VERSION 5.7 ;
  NOWIREEXTENSIONATPIN ON ;
  DIVIDERCHAR "/" ;
  BUSBITCHARS "[]" ;
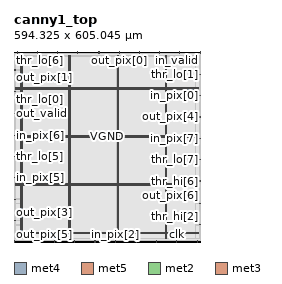
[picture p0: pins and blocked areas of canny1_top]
MACRO canny1_top
  CLASS BLOCK ;
  FOREIGN canny1_top ;
  ORIGIN 0.000 0.000 ;
  SIZE 594.325 BY 605.045 ;
  PIN VGND
    DIRECTION INOUT ;
    USE GROUND ;
    PORT
      LAYER met4 ;
        RECT 24.340 10.640 25.940 593.200 ;
    END
    PORT
      LAYER met4 ;
        RECT 177.940 10.640 179.540 593.200 ;
    END
    PORT
      LAYER met4 ;
        RECT 331.540 10.640 333.140 593.200 ;
    END
    PORT
      LAYER met4 ;
        RECT 485.140 10.640 486.740 593.200 ;
    END
    PORT
      LAYER met5 ;
        RECT 5.280 30.030 589.040 31.630 ;
    END
    PORT
      LAYER met5 ;
        RECT 5.280 183.210 589.040 184.810 ;
    END
    PORT
      LAYER met5 ;
        RECT 5.280 336.390 589.040 337.990 ;
    END
    PORT
      LAYER met5 ;
        RECT 5.280 489.570 589.040 491.170 ;
    END
  END VGND
  PIN VPWR
    DIRECTION INOUT ;
    USE POWER ;
    PORT
      LAYER met4 ;
        RECT 21.040 10.640 22.640 593.200 ;
    END
    PORT
      LAYER met4 ;
        RECT 174.640 10.640 176.240 593.200 ;
    END
    PORT
      LAYER met4 ;
        RECT 328.240 10.640 329.840 593.200 ;
    END
    PORT
      LAYER met4 ;
        RECT 481.840 10.640 483.440 593.200 ;
    END
    PORT
      LAYER met5 ;
        RECT 5.280 26.730 589.040 28.330 ;
    END
    PORT
      LAYER met5 ;
        RECT 5.280 179.910 589.040 181.510 ;
    END
    PORT
      LAYER met5 ;
        RECT 5.280 333.090 589.040 334.690 ;
    END
    PORT
      LAYER met5 ;
        RECT 5.280 486.270 589.040 487.870 ;
    END
  END VPWR
  PIN clk
    DIRECTION INPUT ;
    USE SIGNAL ;
    ANTENNAGATEAREA 1.286700 ;
    ANTENNADIFFAREA 0.434700 ;
    PORT
      LAYER met2 ;
        RECT 518.510 0.000 518.790 4.000 ;
    END
  END clk
  PIN in_pix[0]
    DIRECTION INPUT ;
    USE SIGNAL ;
    ANTENNAGATEAREA 0.126000 ;
    PORT
      LAYER met3 ;
        RECT 590.325 465.840 594.325 466.440 ;
    END
  END in_pix[0]
  PIN in_pix[1]
    DIRECTION INPUT ;
    USE SIGNAL ;
    ANTENNAGATEAREA 0.159000 ;
    PORT
      LAYER met2 ;
        RECT 138.550 601.045 138.830 605.045 ;
    END
  END in_pix[1]
  PIN in_pix[2]
    DIRECTION INPUT ;
    USE SIGNAL ;
    ANTENNAGATEAREA 0.213000 ;
    PORT
      LAYER met2 ;
        RECT 322.090 0.000 322.370 4.000 ;
    END
  END in_pix[2]
  PIN in_pix[3]
    DIRECTION INPUT ;
    USE SIGNAL ;
    ANTENNAGATEAREA 0.159000 ;
    PORT
      LAYER met2 ;
        RECT 193.290 0.000 193.570 4.000 ;
    END
  END in_pix[3]
  PIN in_pix[4]
    DIRECTION INPUT ;
    USE SIGNAL ;
    ANTENNAGATEAREA 0.213000 ;
    PORT
      LAYER met2 ;
        RECT 463.770 601.045 464.050 605.045 ;
    END
  END in_pix[4]
  PIN in_pix[5]
    DIRECTION INPUT ;
    USE SIGNAL ;
    ANTENNAGATEAREA 0.159000 ;
    PORT
      LAYER met3 ;
        RECT 0.000 204.040 4.000 204.640 ;
    END
  END in_pix[5]
  PIN in_pix[6]
    DIRECTION INPUT ;
    USE SIGNAL ;
    ANTENNAGATEAREA 0.213000 ;
    PORT
      LAYER met3 ;
        RECT 0.000 340.040 4.000 340.640 ;
    END
  END in_pix[6]
  PIN in_pix[7]
    DIRECTION INPUT ;
    USE SIGNAL ;
    ANTENNAGATEAREA 0.196500 ;
    PORT
      LAYER met3 ;
        RECT 590.325 329.840 594.325 330.440 ;
    END
  END in_pix[7]
  PIN in_valid
    DIRECTION INPUT ;
    USE SIGNAL ;
    ANTENNAGATEAREA 0.159000 ;
    PORT
      LAYER met2 ;
        RECT 592.570 601.045 592.850 605.045 ;
    END
  END in_valid
  PIN out_pix[0]
    DIRECTION OUTPUT TRISTATE ;
    USE SIGNAL ;
    ANTENNADIFFAREA 0.795200 ;
    PORT
      LAYER met2 ;
        RECT 334.970 601.045 335.250 605.045 ;
    END
  END out_pix[0]
  PIN out_pix[1]
    DIRECTION OUTPUT TRISTATE ;
    USE SIGNAL ;
    ANTENNADIFFAREA 0.795200 ;
    PORT
      LAYER met3 ;
        RECT 0.000 547.440 4.000 548.040 ;
    END
  END out_pix[1]
  PIN out_pix[2]
    DIRECTION OUTPUT TRISTATE ;
    USE SIGNAL ;
    ANTENNADIFFAREA 0.795200 ;
    PORT
      LAYER met2 ;
        RECT 582.910 0.000 583.190 4.000 ;
    END
  END out_pix[2]
  PIN out_pix[3]
    DIRECTION OUTPUT TRISTATE ;
    USE SIGNAL ;
    ANTENNADIFFAREA 0.795200 ;
    PORT
      LAYER met3 ;
        RECT 0.000 68.040 4.000 68.640 ;
    END
  END out_pix[3]
  PIN out_pix[4]
    DIRECTION OUTPUT TRISTATE ;
    USE SIGNAL ;
    ANTENNADIFFAREA 0.445500 ;
    PORT
      LAYER met3 ;
        RECT 590.325 397.840 594.325 398.440 ;
    END
  END out_pix[4]
  PIN out_pix[5]
    DIRECTION OUTPUT TRISTATE ;
    USE SIGNAL ;
    ANTENNADIFFAREA 0.795200 ;
    PORT
      LAYER met2 ;
        RECT 0.090 0.000 0.370 4.000 ;
    END
  END out_pix[5]
  PIN out_pix[6]
    DIRECTION OUTPUT TRISTATE ;
    USE SIGNAL ;
    ANTENNADIFFAREA 0.445500 ;
    PORT
      LAYER met3 ;
        RECT 590.325 122.440 594.325 123.040 ;
    END
  END out_pix[6]
  PIN out_pix[7]
    DIRECTION OUTPUT TRISTATE ;
    USE SIGNAL ;
    ANTENNADIFFAREA 0.795200 ;
    PORT
      LAYER met2 ;
        RECT 399.370 601.045 399.650 605.045 ;
    END
  END out_pix[7]
  PIN out_valid
    DIRECTION OUTPUT TRISTATE ;
    USE SIGNAL ;
    ANTENNADIFFAREA 0.795200 ;
    PORT
      LAYER met3 ;
        RECT 0.000 408.040 4.000 408.640 ;
    END
  END out_valid
  PIN reset
    DIRECTION INPUT ;
    USE SIGNAL ;
    ANTENNAGATEAREA 0.159000 ;
    PORT
      LAYER met2 ;
        RECT 74.150 601.045 74.430 605.045 ;
    END
  END reset
  PIN thr_hi[0]
    DIRECTION INPUT ;
    USE SIGNAL ;
    ANTENNAGATEAREA 0.196500 ;
    PORT
      LAYER met2 ;
        RECT 454.110 0.000 454.390 4.000 ;
    END
  END thr_hi[0]
  PIN thr_hi[1]
    DIRECTION INPUT ;
    USE SIGNAL ;
    ANTENNAGATEAREA 0.213000 ;
    PORT
      LAYER met2 ;
        RECT 528.170 601.045 528.450 605.045 ;
    END
  END thr_hi[1]
  PIN thr_hi[2]
    DIRECTION INPUT ;
    USE SIGNAL ;
    ANTENNAGATEAREA 0.213000 ;
    PORT
      LAYER met3 ;
        RECT 590.325 54.440 594.325 55.040 ;
    END
  END thr_hi[2]
  PIN thr_hi[3]
    DIRECTION INPUT ;
    USE SIGNAL ;
    ANTENNAGATEAREA 0.247500 ;
    PORT
      LAYER met2 ;
        RECT 64.490 0.000 64.770 4.000 ;
    END
  END thr_hi[3]
  PIN thr_hi[4]
    DIRECTION INPUT ;
    USE SIGNAL ;
    ANTENNAGATEAREA 0.213000 ;
    PORT
      LAYER met2 ;
        RECT 128.890 0.000 129.170 4.000 ;
    END
  END thr_hi[4]
  PIN thr_hi[5]
    DIRECTION INPUT ;
    USE SIGNAL ;
    ANTENNAGATEAREA 0.213000 ;
    PORT
      LAYER met3 ;
        RECT 0.000 136.040 4.000 136.640 ;
    END
  END thr_hi[5]
  PIN thr_hi[6]
    DIRECTION INPUT ;
    USE SIGNAL ;
    ANTENNAGATEAREA 0.213000 ;
    PORT
      LAYER met3 ;
        RECT 590.325 193.840 594.325 194.440 ;
    END
  END thr_hi[6]
  PIN thr_hi[7]
    DIRECTION INPUT ;
    USE SIGNAL ;
    ANTENNAGATEAREA 0.213000 ;
    PORT
      LAYER met2 ;
        RECT 257.690 0.000 257.970 4.000 ;
    END
  END thr_hi[7]
  PIN thr_lo[0]
    DIRECTION INPUT ;
    USE SIGNAL ;
    ANTENNAGATEAREA 0.247500 ;
    PORT
      LAYER met3 ;
        RECT 0.000 479.440 4.000 480.040 ;
    END
  END thr_lo[0]
  PIN thr_lo[1]
    DIRECTION INPUT ;
    USE SIGNAL ;
    ANTENNAGATEAREA 0.213000 ;
    PORT
      LAYER met3 ;
        RECT 590.325 533.840 594.325 534.440 ;
    END
  END thr_lo[1]
  PIN thr_lo[2]
    DIRECTION INPUT ;
    USE SIGNAL ;
    ANTENNAGATEAREA 0.247500 ;
    PORT
      LAYER met2 ;
        RECT 202.950 601.045 203.230 605.045 ;
    END
  END thr_lo[2]
  PIN thr_lo[3]
    DIRECTION INPUT ;
    USE SIGNAL ;
    ANTENNAGATEAREA 0.247500 ;
    PORT
      LAYER met2 ;
        RECT 270.570 601.045 270.850 605.045 ;
    END
  END thr_lo[3]
  PIN thr_lo[4]
    DIRECTION INPUT ;
    USE SIGNAL ;
    ANTENNAGATEAREA 0.213000 ;
    PORT
      LAYER met2 ;
        RECT 389.710 0.000 389.990 4.000 ;
    END
  END thr_lo[4]
  PIN thr_lo[5]
    DIRECTION INPUT ;
    USE SIGNAL ;
    ANTENNAGATEAREA 0.247500 ;
    PORT
      LAYER met3 ;
        RECT 0.000 272.040 4.000 272.640 ;
    END
  END thr_lo[5]
  PIN thr_lo[6]
    DIRECTION INPUT ;
    USE SIGNAL ;
    ANTENNAGATEAREA 0.426000 ;
    PORT
      LAYER met2 ;
        RECT 9.750 601.045 10.030 605.045 ;
    END
  END thr_lo[6]
  PIN thr_lo[7]
    DIRECTION INPUT ;
    USE SIGNAL ;
    ANTENNAGATEAREA 0.213000 ;
    PORT
      LAYER met3 ;
        RECT 590.325 261.840 594.325 262.440 ;
    END
  END thr_lo[7]
  OBS
      LAYER li1 ;
        RECT 5.520 10.795 588.800 593.045 ;
      LAYER met1 ;
        RECT 0.070 10.640 592.870 593.200 ;
      LAYER met2 ;
        RECT 0.100 600.765 9.470 601.045 ;
        RECT 10.310 600.765 73.870 601.045 ;
        RECT 74.710 600.765 138.270 601.045 ;
        RECT 139.110 600.765 202.670 601.045 ;
        RECT 203.510 600.765 270.290 601.045 ;
        RECT 271.130 600.765 334.690 601.045 ;
        RECT 335.530 600.765 399.090 601.045 ;
        RECT 399.930 600.765 463.490 601.045 ;
        RECT 464.330 600.765 527.890 601.045 ;
        RECT 528.730 600.765 592.290 601.045 ;
        RECT 0.100 4.280 592.840 600.765 ;
        RECT 0.650 4.000 64.210 4.280 ;
        RECT 65.050 4.000 128.610 4.280 ;
        RECT 129.450 4.000 193.010 4.280 ;
        RECT 193.850 4.000 257.410 4.280 ;
        RECT 258.250 4.000 321.810 4.280 ;
        RECT 322.650 4.000 389.430 4.280 ;
        RECT 390.270 4.000 453.830 4.280 ;
        RECT 454.670 4.000 518.230 4.280 ;
        RECT 519.070 4.000 582.630 4.280 ;
        RECT 583.470 4.000 592.840 4.280 ;
      LAYER met3 ;
        RECT 4.000 548.440 590.325 593.125 ;
        RECT 4.400 547.040 590.325 548.440 ;
        RECT 4.000 534.840 590.325 547.040 ;
        RECT 4.000 533.440 589.925 534.840 ;
        RECT 4.000 480.440 590.325 533.440 ;
        RECT 4.400 479.040 590.325 480.440 ;
        RECT 4.000 466.840 590.325 479.040 ;
        RECT 4.000 465.440 589.925 466.840 ;
        RECT 4.000 409.040 590.325 465.440 ;
        RECT 4.400 407.640 590.325 409.040 ;
        RECT 4.000 398.840 590.325 407.640 ;
        RECT 4.000 397.440 589.925 398.840 ;
        RECT 4.000 341.040 590.325 397.440 ;
        RECT 4.400 339.640 590.325 341.040 ;
        RECT 4.000 330.840 590.325 339.640 ;
        RECT 4.000 329.440 589.925 330.840 ;
        RECT 4.000 273.040 590.325 329.440 ;
        RECT 4.400 271.640 590.325 273.040 ;
        RECT 4.000 262.840 590.325 271.640 ;
        RECT 4.000 261.440 589.925 262.840 ;
        RECT 4.000 205.040 590.325 261.440 ;
        RECT 4.400 203.640 590.325 205.040 ;
        RECT 4.000 194.840 590.325 203.640 ;
        RECT 4.000 193.440 589.925 194.840 ;
        RECT 4.000 137.040 590.325 193.440 ;
        RECT 4.400 135.640 590.325 137.040 ;
        RECT 4.000 123.440 590.325 135.640 ;
        RECT 4.000 122.040 589.925 123.440 ;
        RECT 4.000 69.040 590.325 122.040 ;
        RECT 4.400 67.640 590.325 69.040 ;
        RECT 4.000 55.440 590.325 67.640 ;
        RECT 4.000 54.040 589.925 55.440 ;
        RECT 4.000 10.715 590.325 54.040 ;
      LAYER met4 ;
        RECT 19.615 11.735 20.640 592.105 ;
        RECT 23.040 11.735 23.940 592.105 ;
        RECT 26.340 11.735 174.240 592.105 ;
        RECT 176.640 11.735 177.540 592.105 ;
        RECT 179.940 11.735 327.840 592.105 ;
        RECT 330.240 11.735 331.140 592.105 ;
        RECT 333.540 11.735 481.440 592.105 ;
        RECT 483.840 11.735 484.740 592.105 ;
        RECT 487.140 11.735 579.305 592.105 ;
  END
END canny1_top
END LIBRARY

